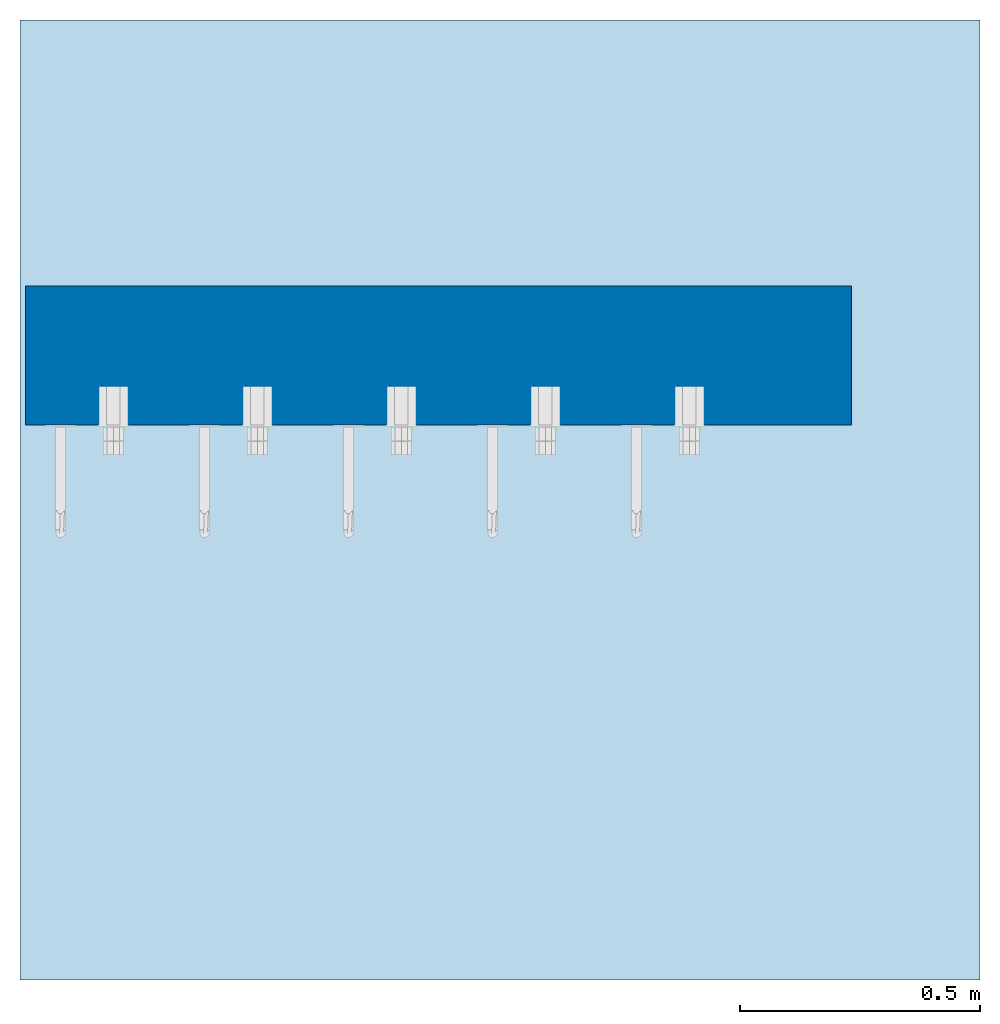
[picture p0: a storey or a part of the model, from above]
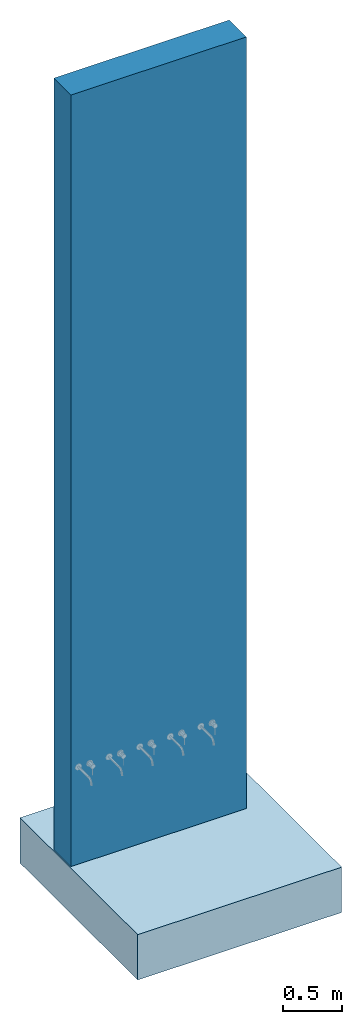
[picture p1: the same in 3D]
Properties of the parts of a building model (IFC2X3)

# File
Description: ViewDefinition [CoordinationView_V2.0]
File name: Project Number
Time: 2023-03-30T10:40:20
Written by: The EXPRESS Data Manager Version 5.02.0100.07 : 28 Aug 2013
Made in: 20220517_1515(x64) - Exporter 20.2.90.12 - Alternate UI 20.2.90.12
Comment: STEP Physical File produced by: The EXPRESS Data Manager Version 5.02.0100.07 : 28 Aug 2013 * Module: EDMstepFileFactory/EDMstandAlone * Creation date: Thu Mar 30 10:40:20 2023 * Host: LAPTOP-F3NQTQR2 * Database: C:\Users\DIANEB~1\AppData\Local\Temp\8d81728e-250a-4cb8-b214-b1ed264e6c72\6bd4aa91-ad02-4150-8251-2cf437168896\ifc * Database version: 5507 * Database creation date: Thu Mar 30 10:40:19 2023 * Schema: IFC2X3 * Model: DataRepository.ifc * Model creation date: Thu Mar 30 10:40:20 2023 * Header model: DataRepository.ifc_HeaderModel * Header model creation date: Thu Mar 30 10:40:20 2023 * EDMuser: sdai-user * EDMgroup: sdai-group * License ID and type: 5605 : Permanent license. Expiry date: * EDMstepFileFactory options: 020000

# IfcProject, Project Number
LongName: Project Name; Phase: Awaiting Approval

# IfcSite, Default
RefLatitude: 51, 30, 23, 112487; RefLongitude: 0, -7, -37, -956022; RefElevation: 0 mm

# IfcBuilding, n/a
LongName: n/a
Pset_BuildingCommon - NumberOfStoreys: 1
Pset_ProductRequirements - Category: Project Information

# IfcBuildingStorey: Level:Circle Head - Project Datum, Level 0
In: n/a
LongName: Level 0; Elevation: 0 mm
Pset_AirSideSystemInformation - Name: Level 0
Pset_ProductRequirements - Name: Level 0; Category: Levels

# IfcDistributionPort (10)
Description: Flow; FlowDirection: SOURCE
Name
2 x Port_435271
2 x Port_435342
2 x Port_435361
2 x Port_435385
2 x Port_435444

# IfcFlowTerminal: DBLTD_Duten_MixerTaps_R377:Brushed Brass, DBLTD_Duten_MixerTaps_R377:Brushed Brass:435271
In: Level 0
Classification: D2010 Plumbing Fixtures (Uniformat); Material: DBLTD_Duten_Metal_BrushedBrass
Pset_DistributionFlowElementCommon - Reference: Brushed Brass; sets with these values: 2
Pset_ElementShading - Color: Brushed Brass
Pset_ManufacturerTypeInformation - ModelReference: Brushed Brass; Manufacturer: contact@duten.fr
Pset_ProductRequirements - Name: Mixer Tap; Category: Plumbing Fixtures

# IfcFlowTerminal: DBLTD_Duten_MixerTaps_R377:Brushed Copper, DBLTD_Duten_MixerTaps_R377:Brushed Copper:435342
In: Level 0
Classification: D2010 Plumbing Fixtures (Uniformat); Material: DBLTD_Duten_Metal_BrushedCopper
Pset_DistributionFlowElementCommon - Reference: Brushed Copper; sets with these values: 2
Pset_ElementShading - Color: Brushed Copper
Pset_ManufacturerTypeInformation - ModelReference: Brushed Copper; Manufacturer: contact@duten.fr
Pset_ProductRequirements - Name: Mixer Tap; Category: Plumbing Fixtures

# IfcFlowTerminal: DBLTD_Duten_MixerTaps_R377:Brushed Stainless Steel, DBLTD_Duten_MixerTaps_R377:Brushed Stainless Steel:435361
In: Level 0
Classification: D2010 Plumbing Fixtures (Uniformat); Material: DBLTD_Duten_Metal_BrushedStainlessSteel
Pset_DistributionFlowElementCommon - Reference: Brushed Stainless Steel; sets with these values: 2
Pset_ElementShading - Color: Brushed Stainless Steel
Pset_ManufacturerTypeInformation - ModelReference: Brushed Stainless Steel; Manufacturer: contact@duten.fr
Pset_ProductRequirements - Name: Mixer Tap; Category: Plumbing Fixtures

# IfcFlowTerminal: DBLTD_Duten_MixerTaps_R377:Chrome, DBLTD_Duten_MixerTaps_R377:Chrome:435385
In: Level 0
Classification: D2010 Plumbing Fixtures (Uniformat); Material: DBLTD_Duten_Metal_Chrome
Pset_DistributionFlowElementCommon - Reference: Chrome; sets with these values: 2
Pset_ElementShading - Color: Chrome
Pset_ManufacturerTypeInformation - ModelReference: Chrome; Manufacturer: contact@duten.fr
Pset_ProductRequirements - Name: Mixer Tap; Category: Plumbing Fixtures

# IfcFlowTerminal: DBLTD_Duten_MixerTaps_R377:Matte Black, DBLTD_Duten_MixerTaps_R377:Matte Black:435444
In: Level 0
Classification: D2010 Plumbing Fixtures (Uniformat); Material: DBLTD_Duten_Metal_MatteBlack
Pset_DistributionFlowElementCommon - Reference: Matte Black; sets with these values: 2
Pset_ElementShading - Color: Matte Black
Pset_ManufacturerTypeInformation - ModelReference: Matte Black; Manufacturer: contact@duten.fr
Pset_ProductRequirements - Name: Mixer Tap; Category: Plumbing Fixtures

# IfcSlab: Floor:Floor-Grnd-Susp_65Scr-80Ins-100Blk-75PC, Floor:Floor-Grnd-Susp_65Scr-80Ins-100Blk-75PC:421633
In: Level 0
Type - PredefinedType: FLOOR; Material: Concrete, Sand/Cement Screed 65 mm, Rigid insulation 80 mm, Air 150 mm, Concrete Masonry, Floor Block 100 mm, Concrete, Precast 75 mm
Type - Pset_ElementShading - Roughness: 914.4 mm
Type - Pset_ProductRequirements - Category: Floors
Type - Pset_QuantityTakeOff - Reference: Floor-Grnd-Susp_65Scr-80Ins-100Blk-75PC
Type - Pset_ReinforcementBarPitchOfSlab - Reference: Floor-Grnd-Susp_65Scr-80Ins-100Blk-75PC
Type - Pset_SlabCommon - Reference: Floor-Grnd-Susp_65Scr-80Ins-100Blk-75PC; IsExternal: no; ThermalTransmittance: 0.117438 kg/K/s3
Pset_QuantityTakeOff - sets with these values: 2
Pset_SlabCommon - LoadBearing: no; PitchAngle: 0 deg

# IfcWallStandardCase: Basic Wall:Wall-Ext_102Bwk-75Ins-100LBlk-12P, Basic Wall:Wall-Ext_102Bwk-75Ins-100LBlk-12P:435260
In: Level 0
Type - PredefinedType: STANDARD; Material: Brick, Common 102.5 mm, Fiberglass Batt 75 mm, Concrete Masonry Units _Low Density 100 mm, Plaster 12.5 mm
Type - Pset_ElementShading - Roughness: 914.4 mm
Type - Pset_ProductRequirements - Category: Walls
Type - Pset_QuantityTakeOff - Reference: Wall-Ext_102Bwk-75Ins-100LBlk-12P
Type - Pset_ReinforcementBarPitchOfWall - Reference: Wall-Ext_102Bwk-75Ins-100LBlk-12P
Type - Pset_WallCommon - IsExternal: no; Reference: Wall-Ext_102Bwk-75Ins-100LBlk-12P; ThermalTransmittance: 0.235926 kg/K/s3
Pset_QuantityTakeOff - sets with these values: 2
Pset_WallCommon - LoadBearing: no; IsExternal: yes; ExtendToStructure: no
